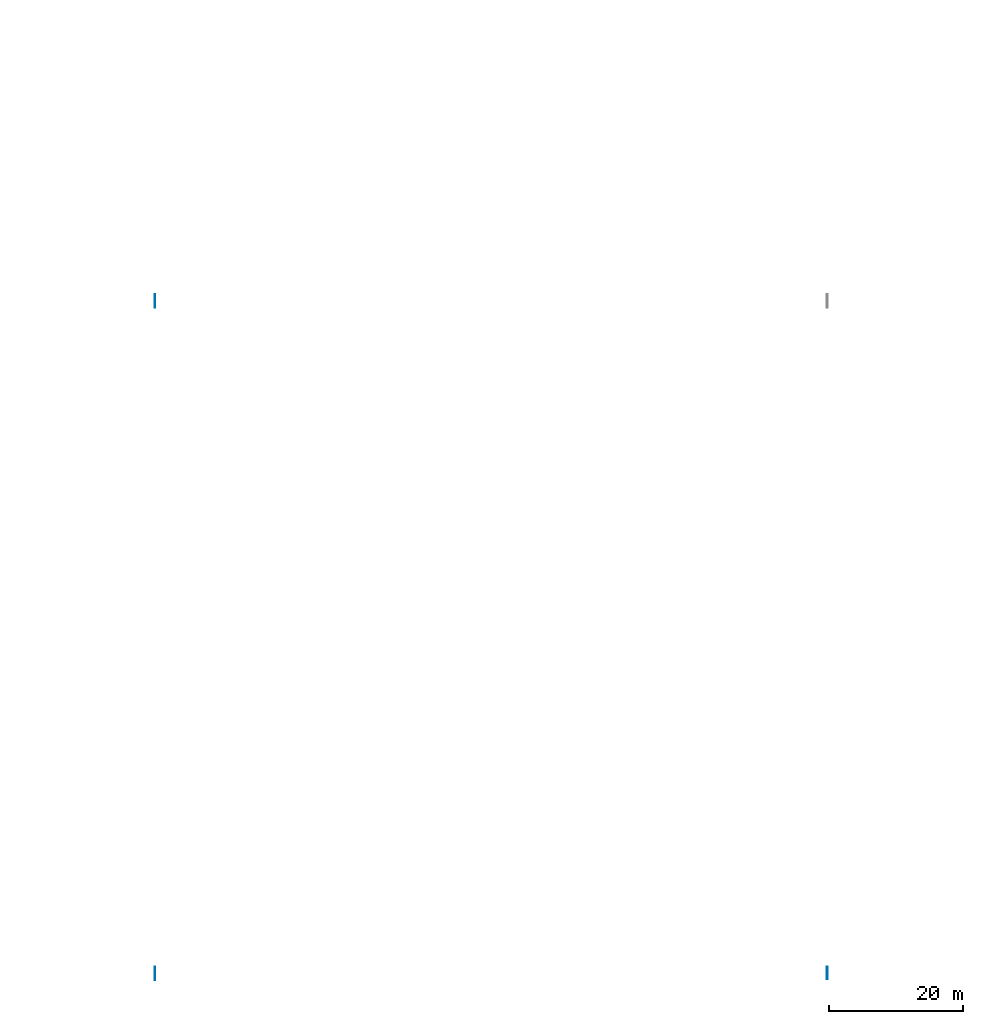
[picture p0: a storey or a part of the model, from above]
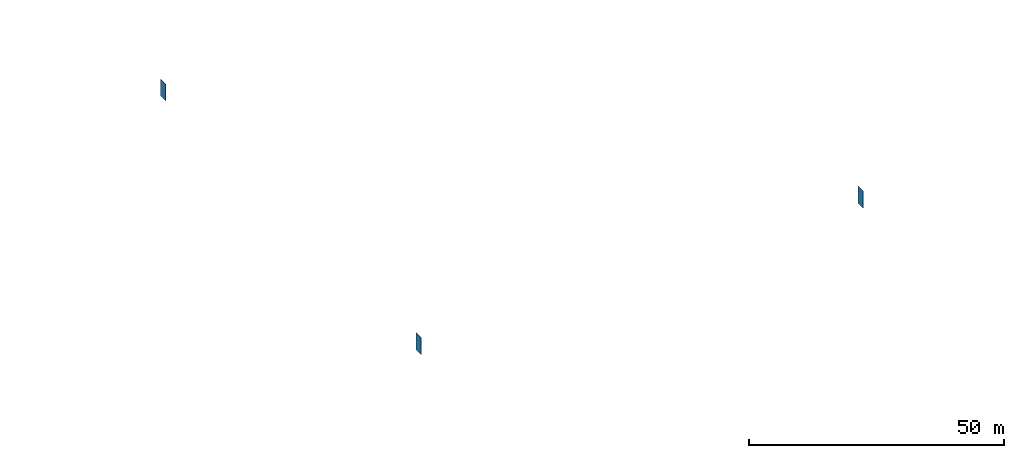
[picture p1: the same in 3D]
Properties of the parts of a building model (IFC2X3)

# File
Description: ViewDefinition [CoordinationView_V2.0]
File name: 0001
Time: 2022-01-20T16:00:44
Written by: The EXPRESS Data Manager Version 5.02.0100.07 : 28 Aug 2013
Made in: 22.0.2.392 - Exporter 22.0.2.392 - Alternate UI 22.0.2.392

# IfcProject, 0001
LongName: Project Name; Phase: Project Status

# IfcSite, Default
RefLatitude: 42, 21, 31, 181945; RefLongitude: -71, -3, -24, -263305; RefElevation: 0 mm
Pset_ProductRequirements - Category: Project Information

# IfcBuilding
Pset_BuildingCommon - NumberOfStoreys: 1
Pset_ProductRequirements - Category: Project Information

# IfcBuildingStorey: Level:8mm Head, Level 1
LongName: Level 1; Elevation: 0 mm
Pset_AirSideSystemInformation - Name: Level 1
Pset_ProductRequirements - Name: Level 1; Category: Levels

# IfcWallStandardCase: Basic Wall:Generic - 100mm (400)
In: Level 1
Type - PredefinedType: STANDARD; Material: Default Wall 100 mm
Type - Pset_ElementShading - Roughness: 914.4 mm
Type - Pset_ProductRequirements - Category: Walls
Type - Pset_WallCommon - IsExternal: yes
Pset_QuantityTakeOff - Reference: Generic - 100mm; sets with these values: 2
Pset_WallCommon - Reference: Generic - 100mm; ExtendToStructure: no; LoadBearing: no
Name (Basic Wall:Generic - 100mm:...)
349228
349270
349305
349308
349311
349314
349317
349320
349323
349326
349329
349332
349335
349338
349341
349344
349347
349350
349353
349356
349364
349366
349372
349374
349376
349378
349380
349382
349384
349386
349388
349390
349392
349394
349396
349398
349400
349402
349404
349406
349434
349436
349442
349444
349446
349448
349450
349452
349454
349456
349458
349460
349462
349464
349466
349468
349470
349472
349474
349476
349480
349482
349488
349490
349492
349494
349496
349498
349500
349502
349504
349506
349508
349510
349512
349514
349516
349518
349520
349522
349526
349528
349534
349536
349538
349540
349542
349544
349546
349548
349550
349552
349554
349556
349558
349560
349562
349564
349566
349568
349572
349574
349580
349582
349584
349586
349588
349590
349592
349594
349596
349598
349600
349602
349604
349606
349608
349610
349612
349614
349618
349620
349626
349628
349630
349632
349634
349636
349638
349640
349642
349644
349646
349648
349650
349652
349654
349656
349658
349660
349664
349666
349672
349674
349676
349678
349680
349682
349684
349686
349688
349690
349692
349694
349696
349698
349700
349702
349704
349706
349710
349712
349718
349720
349722
349724
349726
349728
349730
349732
349734
349736
349738
349740
349742
349744
349746
349748
349750
349752
349756
349758
349764
349766
349768
349770
349772
349774
349776
349778
349780
349782
349784
349786
349788
349790
349792
349794
349796
349798
349802
349804
349810
349812
349814
349816
349818
349820
349822
349824
349826
349828
349830
349832
349834
349836
349838
349840
349842
349844
349848
349850
349856
349858
349860
349862
349864
349866
349868
349870
349872
349874
349876
349878
349880
349882
349884
349886
349888
349890
349894
349896
349902
349904
349906
349908
349910
349912
349914
349916
349918
349920
349922
349924
349926
349928
349930
349932
349934
349936
349940
349942
349948
349950
349952
349954
349956
349958
349960
349962
349964
349966
349968
349970
349972
349974
349976
349978
349980
349982
349986
349988
349994
349996
349998
350000
350002
350004
350006
350008
350010
350012
350014
350016
350018
350020
350022
350024
350026
350028
350032
350034
350040
350042
350044
350046
350048
350050
350052
350054
350056
350058
350060
350062
350064
350066
350068
350070
350072
350074
350078
350080
350086
350088
350090
350092
350094
350096
350098
350100
350102
350104
350106
350108
350110
350112
350114
350116
350118
350120
350124
350126
350132
350134
350136
350138
350140
350142
350144
350146
350148
350150
350152
350154
350156
350158
350160
350162
350164
350166
350170
350172
350178
350180
350182
350184
350186
350188
350190
350192
350194
350196
350198
350200
350202
350204
350206
350208
350210
350212
350216
350218
350224
350226
350228
350230
350232
350234
350236
350238
350240
350242
350244
350246
350248
350250
350252
350254
350256
350258
